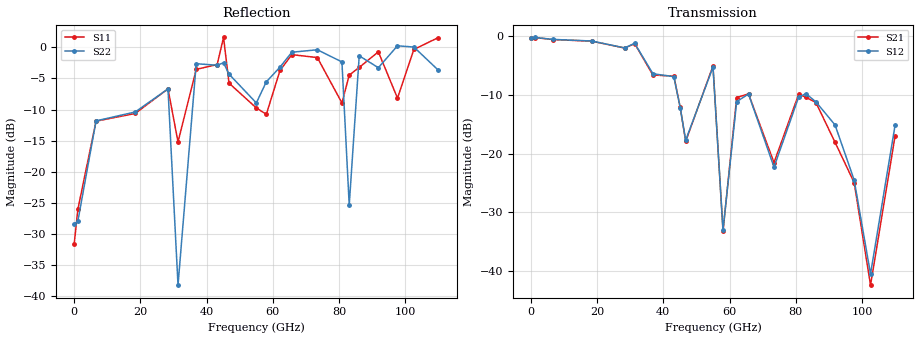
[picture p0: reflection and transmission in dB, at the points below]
!Keysight Technologies,N5247B,US61255204,A.15.70.20
!Date: Friday, October 21, 2022 14:09:26
!Correction: S11(C  4-Port  )
!S31(C  4-Port  )
!S13(C  4-Port  )
!S33(C  4-Port  )
!S2P File: Measurements: S11, S31, S13, S33:
# Hz S  dB  R 50
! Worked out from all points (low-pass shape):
!   401 points, 10 MHz to 110 GHz, reference 50 ohm
!   highest |S21| = -0.19 dB at 1.11 GHz (marker M1); lowest = -42.5 dB at 102.6 GHz (marker M2)
!   |S21| within 3 dB of the highest: start of sweep to 33.82 GHz
!   lowest |S11| = -31.6 dB at 10 MHz (marker M3), VSWR 1.05, Z = 52.7 + j0.0998 ohm
!   |S11| at or under -10 dB: start of sweep to 8.179 GHz; 17.02 GHz to 20.31 GHz (3.299 GHz wide, 17.7 % of centre); 30.04 GHz to 32.58 GHz (2.538 GHz wide, 8.11 % of centre) (the widest 3 of 7)
!   |S22| runs from -39.9 to 0.2 dB; largest |S21 - S12| = 0.15
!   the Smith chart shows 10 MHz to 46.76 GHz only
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1e7  -31.58 2.1  -0.29 -0.2  -0.30 -0.0  -28.37 -5.3
1.1099e9  -26.04 69.9  -0.19 -1.1  -0.17 -1.0  -27.94 107.0
6.6094e9  -11.87 81.3  -0.54 -7.6  -0.51 -7.3  -11.82 75.2
1.843332e10  -10.63 67.9  -0.82 -20.5  -0.79 -20.1  -10.39 66.7
2.833242e10  -6.68 56.1  -1.99 -48.7  -1.97 -47.3  -6.68 34.1
3.135715e10  -15.20 103.4  -1.24 -67.7  -1.18 -66.7  -38.20 26.8
3.685665e10  -3.55 154.4  -6.60 -102.3  -6.37 -102.1  -2.64 172.9
4.318108e10  -2.77 123.9  -6.77 -125.3  -6.88 -124.3  -2.88 155.2
4.51059e10  1.59 78.8  -12.11 -172.3  -12.16 -174.4  -2.49 92.8
4.675575e10  -5.76 66.1  -17.93 -42.0  -17.74 -38.1  -4.31 35.2
5.5005e10  -9.74 179.8  -5.04 160.8  -5.24 160.5  -8.94 152.2
5.802972e10  -10.76 159.7  -33.27 149.2  -33.07 148.3  -5.54 172.7
6.215435e10  -3.72 78.4  -10.44 -164.9  -11.15 -159.1  -3.19 -177.8
6.572902e10  -1.18 13.7  -9.82 129.0  -9.83 149.8  -0.79 33.9
7.342832e10  -1.65 128.2  -21.56 31.4  -22.32 29.5  -0.40 115.3
8.085265e10  -8.94 -92.1  -9.92 20.7  -10.39 21.3  -2.35 -141.7
8.305245e10  -4.47 -47.3  -10.38 -43.2  -9.78 -26.1  -25.34 132.6
8.607718e10  -3.23 6.9  -11.29 -49.6  -11.17 -48.3  -1.37 -14.8
9.185165e10  -0.73 72.4  -18.07 -93.7  -15.12 -90.1  -3.28 68.3
9.762612e10  -8.16 177.8  -24.96 162.6  -24.51 161.1  0.24 167.0
1.025757e11  -0.35 -79.7  -42.47 151.1  -40.56 164.0  0.04 -117.2
1.1e11  1.57 8.9  -16.96 -158.8  -15.12 -163.7  -3.70 15.3
